VERSION 5.7 ;
  NOWIREEXTENSIONATPIN ON ;
  DIVIDERCHAR "/" ;
  BUSBITCHARS "[]" ;
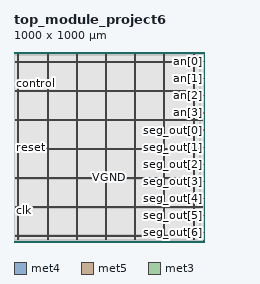
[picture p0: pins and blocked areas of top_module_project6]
MACRO top_module_project6
  CLASS BLOCK ;
  FOREIGN top_module_project6 ;
  ORIGIN 0.000 0.000 ;
  SIZE 1000.000 BY 1000.000 ;
  PIN VGND
    DIRECTION INOUT ;
    USE GROUND ;
    PORT
      LAYER met4 ;
        RECT 24.340 10.640 25.940 987.600 ;
    END
    PORT
      LAYER met4 ;
        RECT 177.940 10.640 179.540 987.600 ;
    END
    PORT
      LAYER met4 ;
        RECT 331.540 10.640 333.140 987.600 ;
    END
    PORT
      LAYER met4 ;
        RECT 485.140 10.640 486.740 987.600 ;
    END
    PORT
      LAYER met4 ;
        RECT 638.740 10.640 640.340 987.600 ;
    END
    PORT
      LAYER met4 ;
        RECT 792.340 10.640 793.940 987.600 ;
    END
    PORT
      LAYER met4 ;
        RECT 945.940 10.640 947.540 987.600 ;
    END
    PORT
      LAYER met5 ;
        RECT 5.280 30.030 994.300 31.630 ;
    END
    PORT
      LAYER met5 ;
        RECT 5.280 183.210 994.300 184.810 ;
    END
    PORT
      LAYER met5 ;
        RECT 5.280 336.390 994.300 337.990 ;
    END
    PORT
      LAYER met5 ;
        RECT 5.280 489.570 994.300 491.170 ;
    END
    PORT
      LAYER met5 ;
        RECT 5.280 642.750 994.300 644.350 ;
    END
    PORT
      LAYER met5 ;
        RECT 5.280 795.930 994.300 797.530 ;
    END
    PORT
      LAYER met5 ;
        RECT 5.280 949.110 994.300 950.710 ;
    END
  END VGND
  PIN VPWR
    DIRECTION INOUT ;
    USE POWER ;
    PORT
      LAYER met4 ;
        RECT 21.040 10.640 22.640 987.600 ;
    END
    PORT
      LAYER met4 ;
        RECT 174.640 10.640 176.240 987.600 ;
    END
    PORT
      LAYER met4 ;
        RECT 328.240 10.640 329.840 987.600 ;
    END
    PORT
      LAYER met4 ;
        RECT 481.840 10.640 483.440 987.600 ;
    END
    PORT
      LAYER met4 ;
        RECT 635.440 10.640 637.040 987.600 ;
    END
    PORT
      LAYER met4 ;
        RECT 789.040 10.640 790.640 987.600 ;
    END
    PORT
      LAYER met4 ;
        RECT 942.640 10.640 944.240 987.600 ;
    END
    PORT
      LAYER met5 ;
        RECT 5.280 26.730 994.300 28.330 ;
    END
    PORT
      LAYER met5 ;
        RECT 5.280 179.910 994.300 181.510 ;
    END
    PORT
      LAYER met5 ;
        RECT 5.280 333.090 994.300 334.690 ;
    END
    PORT
      LAYER met5 ;
        RECT 5.280 486.270 994.300 487.870 ;
    END
    PORT
      LAYER met5 ;
        RECT 5.280 639.450 994.300 641.050 ;
    END
    PORT
      LAYER met5 ;
        RECT 5.280 792.630 994.300 794.230 ;
    END
    PORT
      LAYER met5 ;
        RECT 5.280 945.810 994.300 947.410 ;
    END
  END VPWR
  PIN an[0]
    DIRECTION OUTPUT ;
    USE SIGNAL ;
    ANTENNADIFFAREA 0.445500 ;
    PORT
      LAYER met3 ;
        RECT 996.000 947.960 1000.000 948.560 ;
    END
  END an[0]
  PIN an[1]
    DIRECTION OUTPUT ;
    USE SIGNAL ;
    ANTENNADIFFAREA 0.445500 ;
    PORT
      LAYER met3 ;
        RECT 996.000 858.200 1000.000 858.800 ;
    END
  END an[1]
  PIN an[2]
    DIRECTION OUTPUT ;
    USE SIGNAL ;
    ANTENNADIFFAREA 0.445500 ;
    PORT
      LAYER met3 ;
        RECT 996.000 768.440 1000.000 769.040 ;
    END
  END an[2]
  PIN an[3]
    DIRECTION OUTPUT ;
    USE SIGNAL ;
    ANTENNADIFFAREA 0.445500 ;
    PORT
      LAYER met3 ;
        RECT 996.000 678.680 1000.000 679.280 ;
    END
  END an[3]
  PIN clk
    DIRECTION INPUT ;
    USE SIGNAL ;
    ANTENNAGATEAREA 0.852000 ;
    PORT
      LAYER met3 ;
        RECT 0.000 165.960 4.000 166.560 ;
    END
  END clk
  PIN control
    DIRECTION INPUT ;
    USE SIGNAL ;
    ANTENNAGATEAREA 0.990000 ;
    PORT
      LAYER met3 ;
        RECT 0.000 832.360 4.000 832.960 ;
    END
  END control
  PIN reset
    DIRECTION INPUT ;
    USE SIGNAL ;
    ANTENNAGATEAREA 0.990000 ;
    PORT
      LAYER met3 ;
        RECT 0.000 499.160 4.000 499.760 ;
    END
  END reset
  PIN seg_out[0]
    DIRECTION OUTPUT ;
    USE SIGNAL ;
    ANTENNADIFFAREA 0.445500 ;
    PORT
      LAYER met3 ;
        RECT 996.000 588.920 1000.000 589.520 ;
    END
  END seg_out[0]
  PIN seg_out[1]
    DIRECTION OUTPUT ;
    USE SIGNAL ;
    ANTENNADIFFAREA 0.445500 ;
    PORT
      LAYER met3 ;
        RECT 996.000 499.160 1000.000 499.760 ;
    END
  END seg_out[1]
  PIN seg_out[2]
    DIRECTION OUTPUT ;
    USE SIGNAL ;
    ANTENNADIFFAREA 0.445500 ;
    PORT
      LAYER met3 ;
        RECT 996.000 409.400 1000.000 410.000 ;
    END
  END seg_out[2]
  PIN seg_out[3]
    DIRECTION OUTPUT ;
    USE SIGNAL ;
    ANTENNADIFFAREA 0.445500 ;
    PORT
      LAYER met3 ;
        RECT 996.000 319.640 1000.000 320.240 ;
    END
  END seg_out[3]
  PIN seg_out[4]
    DIRECTION OUTPUT ;
    USE SIGNAL ;
    ANTENNADIFFAREA 0.445500 ;
    PORT
      LAYER met3 ;
        RECT 996.000 229.880 1000.000 230.480 ;
    END
  END seg_out[4]
  PIN seg_out[5]
    DIRECTION OUTPUT ;
    USE SIGNAL ;
    ANTENNADIFFAREA 0.445500 ;
    PORT
      LAYER met3 ;
        RECT 996.000 140.120 1000.000 140.720 ;
    END
  END seg_out[5]
  PIN seg_out[6]
    DIRECTION OUTPUT ;
    USE SIGNAL ;
    ANTENNADIFFAREA 0.445500 ;
    PORT
      LAYER met3 ;
        RECT 996.000 50.360 1000.000 50.960 ;
    END
  END seg_out[6]
  OBS
      LAYER nwell ;
        RECT 5.330 10.795 994.250 987.550 ;
      LAYER li1 ;
        RECT 5.520 10.795 994.060 987.445 ;
      LAYER met1 ;
        RECT 0.990 8.540 994.060 988.000 ;
      LAYER met2 ;
        RECT 1.010 8.510 992.130 988.030 ;
      LAYER met3 ;
        RECT 0.985 948.960 996.000 987.525 ;
        RECT 0.985 947.560 995.600 948.960 ;
        RECT 0.985 859.200 996.000 947.560 ;
        RECT 0.985 857.800 995.600 859.200 ;
        RECT 0.985 833.360 996.000 857.800 ;
        RECT 4.400 831.960 996.000 833.360 ;
        RECT 0.985 769.440 996.000 831.960 ;
        RECT 0.985 768.040 995.600 769.440 ;
        RECT 0.985 679.680 996.000 768.040 ;
        RECT 0.985 678.280 995.600 679.680 ;
        RECT 0.985 589.920 996.000 678.280 ;
        RECT 0.985 588.520 995.600 589.920 ;
        RECT 0.985 500.160 996.000 588.520 ;
        RECT 4.400 498.760 995.600 500.160 ;
        RECT 0.985 410.400 996.000 498.760 ;
        RECT 0.985 409.000 995.600 410.400 ;
        RECT 0.985 320.640 996.000 409.000 ;
        RECT 0.985 319.240 995.600 320.640 ;
        RECT 0.985 230.880 996.000 319.240 ;
        RECT 0.985 229.480 995.600 230.880 ;
        RECT 0.985 166.960 996.000 229.480 ;
        RECT 4.400 165.560 996.000 166.960 ;
        RECT 0.985 141.120 996.000 165.560 ;
        RECT 0.985 139.720 995.600 141.120 ;
        RECT 0.985 51.360 996.000 139.720 ;
        RECT 0.985 49.960 995.600 51.360 ;
        RECT 0.985 10.715 996.000 49.960 ;
      LAYER met4 ;
        RECT 0.790 11.735 20.640 985.825 ;
        RECT 23.040 11.735 23.940 985.825 ;
        RECT 26.340 11.735 174.240 985.825 ;
        RECT 176.640 11.735 177.540 985.825 ;
        RECT 179.940 11.735 327.840 985.825 ;
        RECT 330.240 11.735 331.140 985.825 ;
        RECT 333.540 11.735 481.440 985.825 ;
        RECT 483.840 11.735 484.740 985.825 ;
        RECT 487.140 11.735 635.040 985.825 ;
        RECT 637.440 11.735 638.340 985.825 ;
        RECT 640.740 11.735 788.640 985.825 ;
        RECT 791.040 11.735 791.940 985.825 ;
        RECT 794.340 11.735 942.240 985.825 ;
        RECT 944.640 11.735 945.540 985.825 ;
        RECT 947.940 11.735 983.185 985.825 ;
      LAYER met5 ;
        RECT 0.580 952.310 973.700 981.700 ;
        RECT 0.580 944.210 3.680 952.310 ;
        RECT 0.580 799.130 973.700 944.210 ;
        RECT 0.580 791.030 3.680 799.130 ;
        RECT 0.580 645.950 973.700 791.030 ;
        RECT 0.580 637.850 3.680 645.950 ;
        RECT 0.580 492.770 973.700 637.850 ;
        RECT 0.580 484.670 3.680 492.770 ;
        RECT 0.580 339.590 973.700 484.670 ;
        RECT 0.580 331.490 3.680 339.590 ;
        RECT 0.580 186.410 973.700 331.490 ;
        RECT 0.580 178.310 3.680 186.410 ;
        RECT 0.580 38.300 973.700 178.310 ;
  END
END top_module_project6
END LIBRARY

